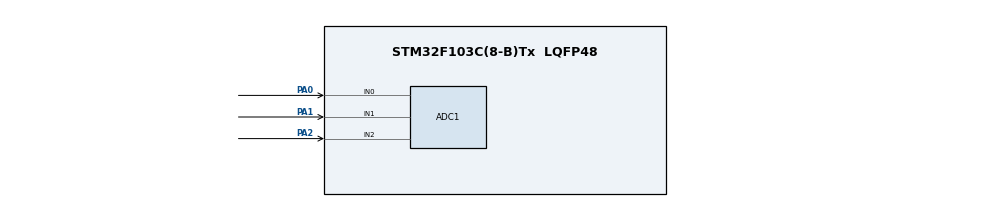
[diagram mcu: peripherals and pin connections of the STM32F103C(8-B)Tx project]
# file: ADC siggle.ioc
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ADC1.Channel-0\#ChannelRegularConversion=ADC_CHANNEL_0
ADC1.NbrOfConversionFlag=1
ADC1.Rank-0\#ChannelRegularConversion=1
ADC1.SamplingTime-0\#ChannelRegularConversion=ADC_SAMPLETIME_239CYCLES_5
ADC1.master=1
Mcu.Family=STM32F1
Mcu.Name=STM32F103C(8-B)Tx
Mcu.Package=LQFP48
NVIC.PriorityGroup=NVIC_PRIORITYGROUP_4
PA0-WKUP.Signal=ADCx_IN0
PA1.Signal=ADCx_IN1
PA13.Mode=Serial_Wire
PA13.Signal=SYS_JTMS-SWDIO
PA14.Mode=Serial_Wire
PA14.Signal=SYS_JTCK-SWCLK
PA2.Signal=ADCx_IN2
PD0-OSC_IN.Mode=HSE-External-Oscillator
PD0-OSC_IN.Signal=RCC_OSC_IN
PD1-OSC_OUT.Mode=HSE-External-Oscillator
PD1-OSC_OUT.Signal=RCC_OSC_OUT
ProjectManager.HeapSize=0x200
ProjectManager.StackSize=0x400
ProjectManager.TargetToolchain=MDK-ARM V5.32
RCC.ADCPresc=RCC_ADCPCLK2_DIV6
RCC.AHBFreq_Value=64000000
RCC.APB1CLKDivider=RCC_HCLK_DIV2
RCC.APB1Freq_Value=32000000
RCC.APB1TimFreq_Value=64000000
RCC.APB2Freq_Value=64000000
RCC.APB2TimFreq_Value=64000000
RCC.HCLKFreq_Value=64000000
RCC.PLLMUL=RCC_PLL_MUL16
RCC.SYSCLKFreq_VALUE=64000000
RCC.SYSCLKSource=RCC_SYSCLKSOURCE_PLLCLK
RCC.USBFreq_Value=64000000
SH.ADCx_IN0.0=ADC1_IN0,IN0
SH.ADCx_IN1.0=ADC1_IN1,IN1
SH.ADCx_IN2.0=ADC1_IN2,IN2
board=custom

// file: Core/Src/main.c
/* USER CODE BEGIN Header */
/**
  ******************************************************************************
  * @file           : main.c
  * @brief          : Main program body
  ******************************************************************************
  * @attention
  *
  * Copyright (c) 2024 STMicroelectronics.
  * All rights reserved.
  *
  * This software is licensed under terms that can be found in the LICENSE file
  * in the root directory of this software component.
  * If no LICENSE file comes with this software, it is provided AS-IS.
  *
  ******************************************************************************
  */
/* USER CODE END Header */
#include "main.h"

ADC_HandleTypeDef hadc1;

void SystemClock_Config(void);
static void MX_GPIO_Init(void);
static void MX_ADC1_Init(void);

/* USER CODE BEGIN 0 */
uint16_t adc_value;
uint16_t adc_value1;
uint16_t get_adc_channel(uint32_t channel)
{
	  uint16_t adc;
		//config channel
		ADC_ChannelConfTypeDef sConfig = {0};
		sConfig.Channel = channel;
		sConfig.Rank = ADC_REGULAR_RANK_1;
		sConfig.SamplingTime = ADC_SAMPLETIME_239CYCLES_5;
		if (HAL_ADC_ConfigChannel(&hadc1, &sConfig) != HAL_OK)
		{
    Error_Handler();
		}
		// read channel
		HAL_ADC_Start(&hadc1);
		HAL_ADC_PollForConversion(&hadc1,1);
		adc = HAL_ADC_GetValue(&hadc1);
		HAL_ADC_Stop(&hadc1);
		return adc;
}
/* USER CODE END 0 */

int main(void)
{

  /* MCU Configuration--------------------------------------------------------*/

  /* Reset of all peripherals, Initializes the Flash interface and the Systick. */
  HAL_Init();

  /* Configure the system clock */
  SystemClock_Config();

  /* Initialize all configured peripherals */
  MX_GPIO_Init();
  MX_ADC1_Init();
  /* USER CODE BEGIN 2 */
		HAL_ADCEx_Calibration_Start(&hadc1);
  /* USER CODE END 2 */

  /* Infinite loop */
  while (1)
  {

    /* USER CODE BEGIN 3 */
		adc_value =  get_adc_channel(ADC_CHANNEL_0);
		adc_value1 = get_adc_channel(ADC_CHANNEL_1);
		HAL_Delay(10);
  }
  /* USER CODE END 3 */
}

void SystemClock_Config(void)
{
  RCC_OscInitTypeDef RCC_OscInitStruct = {0};
  RCC_ClkInitTypeDef RCC_ClkInitStruct = {0};
  RCC_PeriphCLKInitTypeDef PeriphClkInit = {0};

  /** Initializes the RCC Oscillators according to the specified parameters
  * in the RCC_OscInitTypeDef structure.
  */
  RCC_OscInitStruct.OscillatorType = RCC_OSCILLATORTYPE_HSI;
  RCC_OscInitStruct.HSIState = RCC_HSI_ON;
  RCC_OscInitStruct.HSICalibrationValue = RCC_HSICALIBRATION_DEFAULT;
  RCC_OscInitStruct.PLL.PLLState = RCC_PLL_NONE;
  if (HAL_RCC_OscConfig(&RCC_OscInitStruct) != HAL_OK)
  {
    Error_Handler();
  }

  /** Initializes the CPU, AHB and APB buses clocks
  */
  RCC_ClkInitStruct.ClockType = RCC_CLOCKTYPE_HCLK|RCC_CLOCKTYPE_SYSCLK
                              |RCC_CLOCKTYPE_PCLK1|RCC_CLOCKTYPE_PCLK2;
  RCC_ClkInitStruct.SYSCLKSource = RCC_SYSCLKSOURCE_HSI;
  RCC_ClkInitStruct.AHBCLKDivider = RCC_SYSCLK_DIV1;
  RCC_ClkInitStruct.APB1CLKDivider = RCC_HCLK_DIV1;
  RCC_ClkInitStruct.APB2CLKDivider = RCC_HCLK_DIV1;

  if (HAL_RCC_ClockConfig(&RCC_ClkInitStruct, FLASH_LATENCY_0) != HAL_OK)
  {
    Error_Handler();
  }
  PeriphClkInit.PeriphClockSelection = RCC_PERIPHCLK_ADC;
  PeriphClkInit.AdcClockSelection = RCC_ADCPCLK2_DIV2;
  if (HAL_RCCEx_PeriphCLKConfig(&PeriphClkInit) != HAL_OK)
  {
    Error_Handler();
  }
}

static void MX_ADC1_Init(void)
{

  ADC_ChannelConfTypeDef sConfig = {0};

  /** Common config
  */
  hadc1.Instance = ADC1;
  hadc1.Init.ScanConvMode = ADC_SCAN_DISABLE;
  hadc1.Init.ContinuousConvMode = DISABLE;
  hadc1.Init.DiscontinuousConvMode = DISABLE;
  hadc1.Init.ExternalTrigConv = ADC_SOFTWARE_START;
  hadc1.Init.DataAlign = ADC_DATAALIGN_RIGHT;
  hadc1.Init.NbrOfConversion = 1;
  if (HAL_ADC_Init(&hadc1) != HAL_OK)
  {
    Error_Handler();
  }

  /** Configure Regular Channel
  */
  sConfig.Channel = ADC_CHANNEL_0;
  sConfig.Rank = ADC_REGULAR_RANK_1;
  sConfig.SamplingTime = ADC_SAMPLETIME_239CYCLES_5;
  if (HAL_ADC_ConfigChannel(&hadc1, &sConfig) != HAL_OK)
  {
    Error_Handler();
  }

}

static void MX_GPIO_Init(void)
{

  /* GPIO Ports Clock Enable */
  __HAL_RCC_GPIOD_CLK_ENABLE();
  __HAL_RCC_GPIOA_CLK_ENABLE();

}

void Error_Handler(void)
{
  __disable_irq();
  while (1)
  {
  }
}
